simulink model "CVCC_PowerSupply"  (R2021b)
settings: Solver=VariableStepAuto  StartTime=0.0  StopTime=0.025  RelTol=1e-3
libraries: fl_lib x12, nesl_utility x6, ee_lib x3

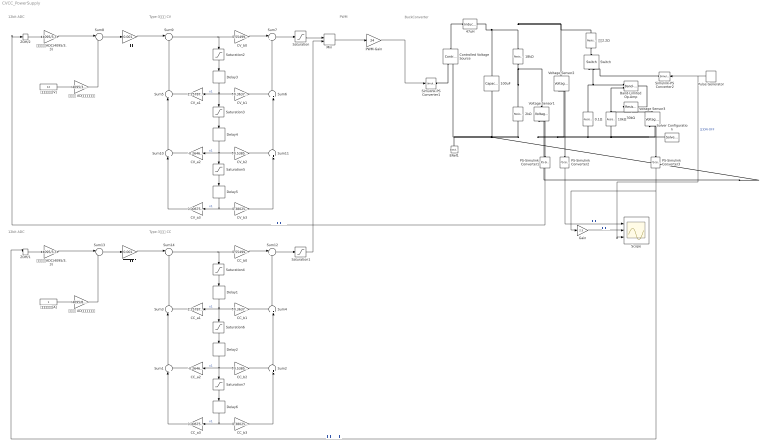
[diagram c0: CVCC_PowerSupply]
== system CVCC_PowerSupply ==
  note: Type-3補償器 CV
  note: BuckConverter
  note: 12bit ADC
  note: PWM
  note: 12bit ADC
  note: Type-3補償器 CC
  0.1Ω : fl_lib/Electrical/Electrical Elements/Resistor  R=0.1 Ohm  i_specify=off  i_priority=None  i=0 A  i_nominal_specify=off  i_nominal_unit=A  i_nominal_value=1  v_specify=off  v_priority=None  v=0 V  v_nominal_specify=off  v_nominal_unit=V  v_nominal_value=1
  100uF : ee_lib/Passive/Capacitor  cap_option=0  c=91.060 uF  Cvec=[1e-05, 1e-06] F  Vvec=[0, 10] V  CV_table_symmetry=1  f_vec=[1, 10] kHz  DFext_vec=[.8, 1.2]  C_tol=5  enable_C_tol=0  tol_distribution=1  nSigma=4  r=569.22e-3 Ohm  g=0 1/Ohm  averaging_period=0 s  enable_operating_limits=0  operating_limit_action=2  max_working_voltage_range=[-25, 25] V  power_rating=1 W  enable_faults=0  fault_action=1  Cscale_faulted=100  R_faulted=1e-3 Ohm  G_faulted=0 1/Ohm  tau_fault=1e-3 s  enable_temporal_fault=0  t_fault=1 s  enable_behavioral_fault=0  max_permissible_voltage_range=[-100, 100] V  t_fail_on_voltage=1 s  i_specify=off  i_priority=None  i=0 A  i_nominal_specify=off  i_nominal_unit=A  i_nominal_value=1  v_specify=off  v_priority=None  v=0 V  v_nominal_specify=off  v_nominal_unit=V  v_nominal_value=1  vc_specify=off  vc_priority=High  vc=0 V  vc_nominal_specify=off  vc_nominal_unit=V  vc_nominal_value=1
  10kΩ : fl_lib/Electrical/Electrical Elements/Resistor  R=10 kOhm  i_specify=off  i_priority=None  i=0 A  i_nominal_specify=off  i_nominal_unit=A  i_nominal_value=1  v_specify=off  v_priority=None  v=0 V  v_nominal_specify=off  v_nominal_unit=V  v_nominal_value=1
  18kΩ : fl_lib/Electrical/Electrical Elements/Resistor  R=18 kOhm  i_specify=off  i_priority=None  i=0 A  i_nominal_specify=off  i_nominal_unit=A  i_nominal_value=1  v_specify=off  v_priority=None  v=0 V  v_nominal_specify=off  v_nominal_unit=V  v_nominal_value=1
  2kΩ : fl_lib/Electrical/Electrical Elements/Resistor  R=2 kOhm  i_specify=off  i_priority=None  i=0 A  i_nominal_specify=off  i_nominal_unit=A  i_nominal_value=1  v_specify=off  v_priority=None  v=0 V  v_nominal_specify=off  v_nominal_unit=V  v_nominal_value=1
  30kΩ : fl_lib/Electrical/Electrical Elements/Resistor  R=30 kOhm  i_specify=off  i_priority=None  i=0 A  i_nominal_specify=off  i_nominal_unit=A  i_nominal_value=1  v_specify=off  v_priority=None  v=0 V  v_nominal_specify=off  v_nominal_unit=V  v_nominal_value=1
  47uH : ee_lib/Passive/Inductor  l=45.714 uH  L_tol=20  enable_L_tol=0  tol_distribution=1  nSigma=4  r=23.88e-3 Ohm  g=1e-9 1/Ohm  enable_operating_limits=0  operating_limit_action=2  max_working_current=1 A  power_rating=1 W  enable_faults=0  fault_action=1  lambdaPercent=50  k_faulted=0.9999  turnsShort=0  openCct=0  groundShort=0  groundShortG=0 1/Ohm  tau_fault=1e-3 s  enable_temporal_fault=0  t_fault=1 s  enable_behavioral_fault=0  max_permissible_voltage=100 V  n_fail_on_voltage=1  max_permissible_current=1 A  t_fail_on_current=1 s  i_L_specify=off  i_L_priority=High  i_L=0 A  i_L_nominal_specify=off  i_L_nominal_unit=A  i_L_nominal_value=1
  Band-Limited Op-Amp : ee_lib/Integrated Circuits/Band-Limited Op-Amp  A=1000  Rin=10 GOhm  Rout=1 Ohm  Vmin=0 V  Vmax=3.3 V  Vdotmax=160000 V/s  f=350 kHz  V0=0 V
  CC_a1 : Gain  Gain=1.257873708494
  CC_a2 : Gain  Gain=-0.264633152863
  CC_a3 : Gain  Gain=0.006759444370
  CC_b0 : Gain  Gain=0.554999476184
  CC_b1 : Gain  Gain=-0.363790613663
  CC_b2 : Gain  Gain=-0.538530618700
  CC_b3 : Gain  Gain=0.380259471146
  CV_a1 : Gain  Gain=1.257873708494
  CV_a2 : Gain  Gain=-0.264633152863
  CV_a3 : Gain  Gain=0.006759444370
  CV_b0 : Gain  Gain=0.554999476184
  CV_b1 : Gain  Gain=-0.363790613663
  CV_b2 : Gain  Gain=-0.538530618700
  CV_b3 : Gain  Gain=0.380259471146
  Controlled Voltage Source : fl_lib/Electrical/Electrical Sources/Controlled Voltage Source
  Delay{1..6} (6 alike) : Delay  DelayLength=1  InitialCondition=0
  ERef1 : fl_lib/Electrical/Electrical Elements/Electrical Reference
  Gain : Gain  Gain=2.5
  Min : MinMax  Inputs=2
  PS-Simulink Converter1 : nesl_utility/PS-Simulink Converter  PhysicalDomain=network_engine_domain  SubClassName=ps_output  LeftPortType=input  RightPortType=output  PseudoPeriodic=off  Frequencies=[]  Unit=1  AffineConversion=off
  PS-Simulink Converter2 : nesl_utility/PS-Simulink Converter  PhysicalDomain=network_engine_domain  SubClassName=ps_output  LeftPortType=input  RightPortType=output  PseudoPeriodic=off  Frequencies=[]  Unit=1  AffineConversion=off
  PS-Simulink Converter3 : nesl_utility/PS-Simulink Converter  PhysicalDomain=network_engine_domain  SubClassName=ps_output  LeftPortType=input  RightPortType=output  PseudoPeriodic=off  Frequencies=[]  Unit=1  AffineConversion=off
  PWM-Gain : Gain  Gain=24  OutDataTypeStr=double
  Pulse Generator : DiscretePulseGenerator  PulseType=Time based  Period=0.01  PulseWidth=50  PhaseDelay=0.005
  Saturation : Saturate  UpperLimit=1.0  LowerLimit=0.0
  Saturation1 : Saturate  UpperLimit=1.0  LowerLimit=0.0
  Saturation{2..7} (6 alike) : Saturate  UpperLimit=20  LowerLimit=-inf
  Scope : Scope  NumInputPorts=3
  Simulink-PS Converter1 : nesl_utility/Simulink-PS Converter  PhysicalDomain=network_engine_domain  SubClassName=ps_input  LeftPortType=input  RightPortType=output  PseudoPeriodic=off  Frequencies=[]  NoiseDistribution=none  NoiseParameters=[]  Unit=V  AffineConversion=off  FilteringAndDerivatives=zero  SimscapeFilterOrder=1  InputFilterTimeConstant=.001  UdotUserProvided=0
  Simulink-PS Converter2 : nesl_utility/Simulink-PS Converter  PhysicalDomain=network_engine_domain  SubClassName=ps_input  LeftPortType=input  RightPortType=output  PseudoPeriodic=off  Frequencies=[]  NoiseDistribution=none  NoiseParameters=[]  Unit=1  AffineConversion=off  FilteringAndDerivatives=provide  SimscapeFilterOrder=1  InputFilterTimeConstant=0.001  UdotUserProvided=0
  Solver Configuration : nesl_utility/Solver Configuration  PhysicalDomain=network_engine_domain  SubClassName=solver  LeftPortType=input  RightPortType=generic  Tones=[]  Harmonics=[]  SimulateNoise=off  Profile=off  UseLocalSampling=off  EnableSwitchedLinearOptims=on  FrequencyDomain=off  UseCCode=off  RelTol=0.001  AbsTol=1e-06  MinStep=1e-09  ToWorkspace=off  RevertToSquareIcSolve=off  NumHomotopyIterations=100  PhasorMode=off  PhasorModeNumHarmonics=1  DoDC=on  ResidualTolerance=1e-9  UseLocalSolver=off  LocalSolverChoice=NE_BACKWARD_EULER_ADVANCER  LocalSolverSampleTime=.001  DoFixedCost=off  MaxNonlinIter=3  MaxModeIter=2  ComputeImpulses=off  ImpulseIterations=2  LinearAlgebra=Sparse  EquationFormulation=NE_TIME_EF  DelaysMemoryBudget=1024  AutomaticFiltering=on  FilteringTimeConstant=0.001  PartitionStorageMethod=AS_NEEDED  PartitionMemoryBudget=1024  PartitionMethod=FAST
  Sum{1,3,5,7,9..10,12,14} (8 alike) : Sum  Inputs=|++
  Sum{2,4,6,11} (4 alike) : Sum  Inputs=++|
  Sum13 : Sum  Inputs=|-+  InputSameDT=on  SaturateOnIntegerOverflow=on
  Sum8 : Sum  Inputs=|-+  InputSameDT=on  SaturateOnIntegerOverflow=on
  Switch : fl_lib/Electrical/Electrical Elements/Switch  R_closed=0.01 Ohm  G_open=1e-8 1/Ohm  Threshold=0.5  i_specify=off  i_priority=None  i=0 A  i_nominal_specify=off  i_nominal_unit=A  i_nominal_value=1  v_specify=off  v_priority=None  v=0 V  v_nominal_specify=off  v_nominal_unit=V  v_nominal_value=1
  Voltage Sensor1 : fl_lib/Electrical/Electrical Sensors/Voltage Sensor
  Voltage Sensor2 : fl_lib/Electrical/Electrical Sensors/Voltage Sensor
  Voltage Sensor3 : fl_lib/Electrical/Electrical Sensors/Voltage Sensor
  ZOH/1 : ZeroOrderHold  SampleTime=10e-6
  ZOH/2 : ZeroOrderHold  SampleTime=10e-6
  出力電圧基準[V] : Constant  Value=12
  出力電流基準[A] : Constant
  "負荷2.2Ω " : fl_lib/Electrical/Electrical Elements/Resistor  R=2.2 Ohm  i_specify=off  i_priority=None  i=0 A  i_nominal_specify=off  i_nominal_unit=A  i_nominal_value=1  v_specify=off  v_priority=None  v=0 V  v_nominal_specify=off  v_nominal_unit=V  v_nominal_value=1
  電圧ゲイン調整 : Gain  Gain=0.001
  電圧基準 AD値変換用ゲイン : Gain  Gain=4095/3.3/10
  電圧検出用ADC(4095/3.3) : Gain  Gain=4095/3.3  OutMin=0  OutMax=4095
  電流ゲイン調整 : Gain  Gain=0.001
  電流基準 AD値変換用ゲイン : Gain  Gain=4095/8.25
  電流検出用ADC(4095/3.3) : Gain  Gain=4095/3.3  OutMin=0  OutMax=4095
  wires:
  出力電圧基準[V]/1 -> 電圧基準 AD値変換用ゲイン/1
  Min/1 -> PWM-Gain/1
  PS-Simulink Converter2/1 -> Scope/1  "出力電圧"
  PWM-Gain/1 -> Simulink-PS Converter1/1
  電圧基準 AD値変換用ゲイン/1 -> Sum8/2
  ZOH/2/1 -> 電圧検出用ADC(4095/3.3)/1
  電圧検出用ADC(4095/3.3)/1 -> Sum8/1
  Sum8/1 -> 電圧ゲイン調整/1
  PS-Simulink Converter1/1 -> ZOH/2/1  "電圧フィードバック"
  Sum13/1 -> 電流ゲイン調整/1
  出力電流基準[A]/1 -> 電流基準 AD値変換用ゲイン/1
  ZOH/1/1 -> 電流検出用ADC(4095/3.3)/1
  電流検出用ADC(4095/3.3)/1 -> Sum13/1
  電流基準 AD値変換用ゲイン/1 -> Sum13/2
  PS-Simulink Converter3/1 -> Gain/1, ZOH/1/1  "電流フィードバック"
  Pulse Generator/1 -> Simulink-PS Converter2/1, Scope/3  "負荷ON-OFF"
  Saturation1/1 -> Min/2
  Saturation/1 -> Min/1
  Gain/1 -> Scope/2  "出力電流"
  Sum7/1 -> Saturation/1
  電圧ゲイン調整/1 -> Sum9/1
  CV_a2/1 -> Sum10/2
  Sum11/1 -> Sum6/2
  Saturation2/1 -> Delay3/1
  Delay5/1 -> CV_a3/1, CV_b3/1  "x1"
  CV_b0/1 -> Sum7/1
  Sum9/1 -> Saturation2/1, CV_b0/1
  Sum10/1 -> Sum5/1
  CV_b2/1 -> Sum11/1
  Saturation5/1 -> Delay5/1
  Saturation3/1 -> Delay4/1
  Delay3/1 -> Saturation3/1, CV_a1/1, CV_b1/1  "x1"
  Sum5/1 -> Sum9/2
  CV_a3/1 -> Sum10/1
  CV_b1/1 -> Sum6/1
  Sum6/1 -> Sum7/2
  CV_a1/1 -> Sum5/2
  Delay4/1 -> Saturation5/1, CV_a2/1, CV_b2/1  "x1"
  CV_b3/1 -> Sum11/2
  CC_a2/1 -> Sum1/2
  Sum2/1 -> Sum4/2
  Saturation4/1 -> Delay1/1
  Delay2/1 -> Saturation7/1, CC_a2/1, CC_b2/1  "x1"
  Delay6/1 -> CC_a3/1, CC_b3/1  "x1"
  Sum14/1 -> Saturation4/1, CC_b0/1
  CC_b0/1 -> Sum12/1
  Delay1/1 -> Saturation6/1, CC_a1/1, CC_b1/1  "x1"
  Sum1/1 -> Sum3/1
  CC_b2/1 -> Sum2/1
  Saturation7/1 -> Delay6/1
  Saturation6/1 -> Delay2/1
  Sum3/1 -> Sum14/2
  Sum12/1 -> Saturation1/1
  CC_b1/1 -> Sum4/1
  CC_a3/1 -> Sum1/1
  電流ゲイン調整/1 -> Sum14/1
  CC_a1/1 -> Sum3/2
  Sum4/1 -> Sum12/2
  CC_b3/1 -> Sum2/2
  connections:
  18kΩ/RConn1 -- 2kΩ/LConn1 -- Voltage Sensor1/LConn1
  Voltage Sensor3/RConn2 -- Solver Configuration/RConn1 -- 10kΩ/RConn1 -- 0.1Ω/RConn1 -- Voltage Sensor2/RConn2 -- Voltage Sensor1/RConn2 -- 2kΩ/RConn1 -- 100uF/RConn1 -- ERef1/LConn1 -- Controlled Voltage Source/RConn2
  18kΩ/LConn1 -- "負荷2.2Ω "/LConn1 -- Voltage Sensor2/LConn1 -- 100uF/LConn1 -- 47uH/RConn1
  Controlled Voltage Source/RConn1 -- Simulink-PS Converter1/RConn1
  Controlled Voltage Source/LConn1 -- 47uH/LConn1
  PS-Simulink Converter1/LConn1 -- Voltage Sensor1/RConn1
  PS-Simulink Converter2/LConn1 -- Voltage Sensor2/RConn1
  10kΩ/LConn1 -- 30kΩ/LConn1 -- Band-Limited Op-Amp/LConn2
  PS-Simulink Converter3/LConn1 -- Voltage Sensor3/RConn1
  30kΩ/RConn1 -- Band-Limited Op-Amp/RConn1 -- Voltage Sensor3/LConn1
  Band-Limited Op-Amp/LConn1 -- Switch/RConn2 -- 0.1Ω/LConn1
  Simulink-PS Converter2/RConn1 -- Switch/RConn1
  Switch/LConn1 -- "負荷2.2Ω "/RConn1
